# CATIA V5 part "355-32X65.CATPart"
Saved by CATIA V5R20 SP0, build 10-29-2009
Part number: 355-32X65
Definition: NONE
Nomenclature: 355-32X65
Source: Unknown
Description: 355-32X65
Bounding box of the stored display mesh (mm): x -32 to 33, y -22.5 to 22.5, z -22.5 to 22.5
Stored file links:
  C:\Users\Utente\Desktop\IO LAVORO\3D X SITO CF\X SITO\PLASTICA\355\355-32X65.CATPart

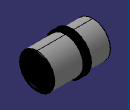
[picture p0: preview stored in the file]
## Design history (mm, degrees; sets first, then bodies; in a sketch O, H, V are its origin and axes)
Body1 "355-32X65" (main body)
  Solid1: solid without history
